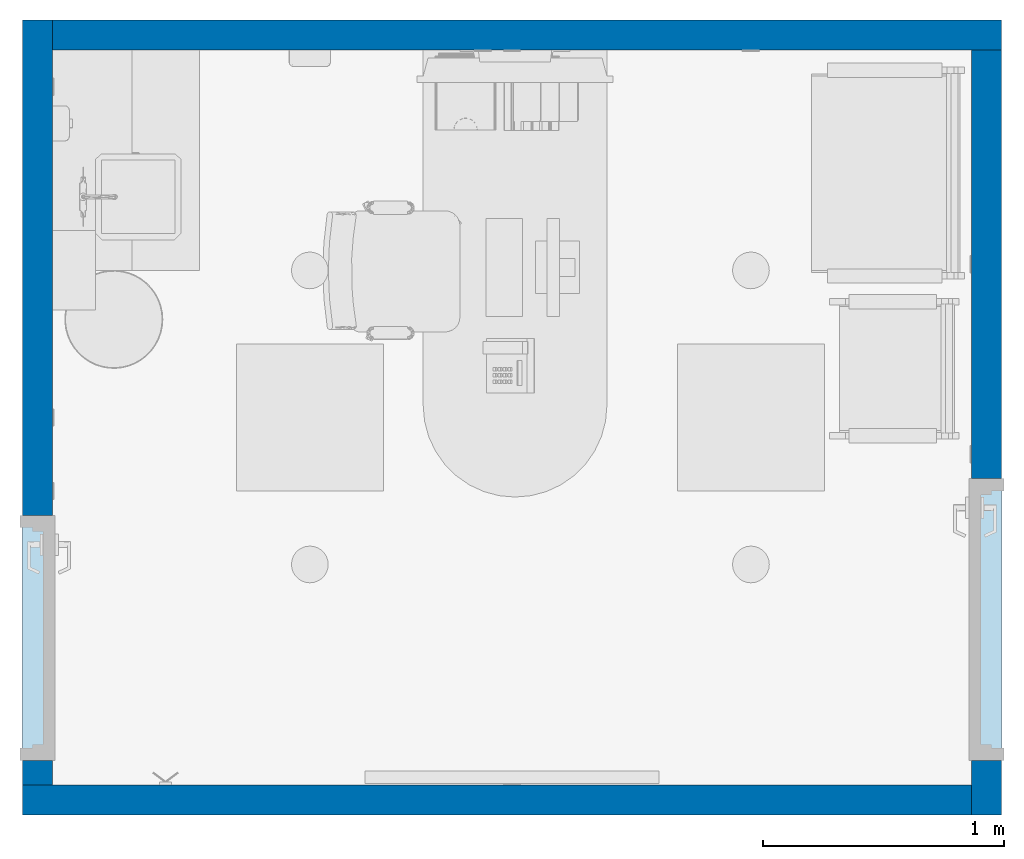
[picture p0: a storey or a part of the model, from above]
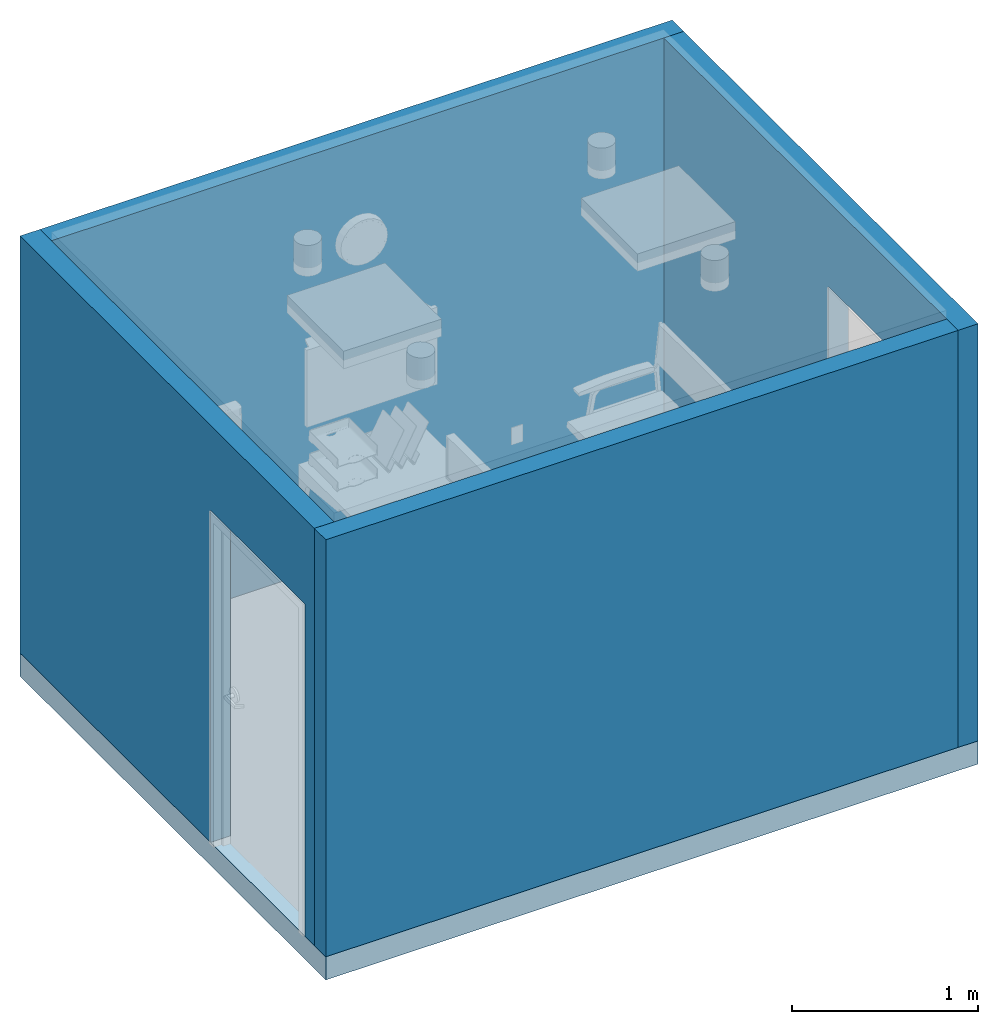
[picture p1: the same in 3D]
Properties of the parts of a building model (IFC2X3)

# File
Description: ViewDefinition [CoordinationView_V2.0]
File name: (ROOM CODE)
Time: 2018-06-27T16:41:24
Written by: The EXPRESS Data Manager Version 5.02.0100.07 : 28 Aug 2013
Made in: 20170223_1515(x64) - Exporter 18.0.0.420 - Alternate UI 18.0.0.420
Comment: STEP Physical File produced by: The EXPRESS Data Manager Version 5.02.0100.07 : 28 Aug 2013 * Module: EDMstepFileFactory/EDMstandAlone * Creation date: Wed Jun 27 16:41:24 2018 * Host: L106-OKC * Database: C:\Users\BHR~1.SPU\AppData\Local\Temp\{47063BCD-B4B2-4790-9621-44DDCE2818D9}\ifc * Database version: 5507 * Database creation date: Wed Jun 27 16:41:22 2018 * Schema: IFC2X3 * Model: DataRepository.ifc * Model creation date: Wed Jun 27 16:41:22 2018 * Header model: DataRepository.ifc_HeaderModel * Header model creation date: Wed Jun 27 16:41:22 2018 * EDMuser: sdai-user * EDMgroup: sdai-group * License ID and type: 5605 : Permanent license. Expiry date: * EDMstepFileFactory options: 020000

# IfcProject, (ROOM CODE)
LongName: ROOM NAME (ROOM CODE); Phase: DRAFT

# IfcSite, Default
RefLatitude: 42, 21, 31, 181945; RefLongitude: -71, -3, -24, -263305; RefElevation: 0 ft

# IfcBuilding, OUTPATIENT / PACT CLINIC (Ch. 265)
LongName: OUTPATIENT / PACT CLINIC (Ch. 265)
Pset_BuildingCommon - NumberOfStoreys: 1

# IfcBuildingStorey, DATUM
In: OUTPATIENT / PACT CLINIC (Ch. 265)
LongName: DATUM; Elevation: 0 ft

# IfcSpace, OFDC2
In: DATUM
LongName: CONSULT ROOM; InteriorOrExteriorSpace: INTERNAL
Pset_SpaceCommon - Reference: CONSULT ROOM OFDC2; Category: Rooms

# IfcBuildingElementProxy: 24" x 24", Supply Diffuser:24" x 24":774819
In: OFDC2
Type - Classification: D3040100 Air Distribution Systems (Uniformat)
Pset_BuildingElementProxyCommon - Reference: 24" x 24"

# IfcBuildingElementProxy: 24" x 24", Return Register:24" x 24":774793
In: OFDC2
Type - Classification: D3040200 Exhaust Ventilation Systems (Uniformat)
Pset_BuildingElementProxyCommon - Reference: 24" x 24"

# IfcBuildingElementProxy: A1015 Telephone_Desk Multi-Line, A1015 - Telephone, Desk, Multiple Line:A1015 Telephone_Desk Multi-Line:1867700
In: OFDC2
Type - Classification: VV (Uniformat)
Pset_BuildingElementProxyCommon - Reference: A1015 Telephone_Desk Multi-Line

# IfcBuildingElementProxy: A5075 - Dispenser, Soap, A5075 - Dispenser, Soap:A5075 - Dispenser, Soap:1867712
In: OFDC2
Classification: VV (Uniformat)
Pset_BuildingElementProxyCommon - Reference: A5075 - Dispenser, Soap

# IfcBuildingElementProxy: A5077 Dispenser_Hand Sanitzer, Hands free, A5077 Dispenser_Hand Sanitzer, Hands free:A5077 Dispenser_Hand Sanitzer, Hands free:1867705
In: OFDC2
Type - Classification: VV (Uniformat)
Pset_BuildingElementProxyCommon - Reference: A5077 Dispenser_Hand Sanitzer, Hands free

# IfcBuildingElementProxy: A5080 - Dispenser, Paper Towel, A5080 - Dispenser, Paper Towel:A5080 - Dispenser, Paper Towel:1867711
In: OFDC2
Classification: CC (Uniformat)
Pset_BuildingElementProxyCommon - Reference: A5080 - Dispenser, Paper Towel

# IfcBuildingElementProxy: A5145 - Hook, Garment, Double, A5145 - Hook, Garment, Double:A5145 - Hook, Garment, Double:1867715
In: OFDC2
Type - Classification: CC (Uniformat)
Pset_BuildingElementProxyCommon - Reference: A5145 - Hook, Garment, Double

# IfcBuildingElementProxy: A5212 - Bracket, Television, Wall-Mounted, Tilt/Angle 32"x 4", A5212 - Bracket, Television, Wall-Mounted, TiltAngle 32x 4:A5212 - Bracket, Television, Wall-Mounted, Tilt/Angle 32"x 4":1867704
In: OFDC2
Type - Classification: VV (Uniformat)
Pset_BuildingElementProxyCommon - Reference: A5212 - Bracket, Television, Wall-Mounted, Tilt/Angle 32"x 4"

# IfcBuildingElementProxy: A5220 - Bracket, Television, Wall Backing, A5220 - Bracket, Television, Wall Backing:A5220 - Bracket, Television, Wall Backing:1867703
In: OFDC2
Type - Classification: CC (Uniformat)
Pset_BuildingElementProxyCommon - Reference: A5220 - Bracket, Television, Wall Backing

# IfcBuildingElementProxy: CD040 - Cabinet, W-H, 2 Shelf, 2 DO, Sloping Top, 38x36x13, CD040 - Cabinet, W-H, 2 Shelf, 2 DO, Sloping Top, 38x36x13:CD040 - Cabinet, W-H, 2 Shelf, 2 DO, Sloping Top, 38x36x13:1867713
In: OFDC2
Type - Classification: CC (Uniformat)
Pset_BuildingElementProxyCommon - Reference: CD040 - Cabinet, W-H, 2 Shelf, 2 DO, Sloping Top, 38x36x13

# IfcBuildingElementProxy: CS010 - Sink, SS, Single Compartment, 7.5x12x12 ID, CS010 - Sink, SS, Single Compartment, 7.5x12x12 ID:CS010 - Sink, SS, Single Compartment, 7.5x12x12 ID:1867710
In: OFDC2
Type - Classification: CC (Uniformat)
Pset_BuildingElementProxyCommon - Reference: CS010 - Sink, SS, Single Compartment, 7.5x12x12 ID

# IfcBuildingElementProxy: CT020 - Countertop, Solid Surface, CT020 - Countertop, Solid Surface:CT020 - Countertop, Solid Surface:1867709
In: OFDC2
Type - Classification: CC (Uniformat)
Pset_BuildingElementProxyCommon - Reference: CT020 - Countertop, Solid Surface

# IfcBuildingElementProxy: Duplex (6)
In: OFDC2
Pset_BuildingElementProxyCommon - Reference: Duplex
Name (Outlet, Duplex, Wall:Duplex:...)
1523865
1532874
1533012
1533116
1870652
1941387

# IfcBuildingElementProxy: E0063 - Workstation, L-Shaped wPeninsula, Wall Mtd, 72x72 (1), E0063 - Workstation, L-Shaped wPeninsula, Wall Mtd, 72x72 (1):E0063 - Workstation, L-Shaped wPeninsula, Wall Mtd, 72x72 (1):1867707
In: OFDC2
Pset_BuildingElementProxyCommon - Reference: E0063 - Workstation, L-Shaped wPeninsula, Wall Mtd, 72x72 (1)

# IfcBuildingElementProxy: F0205 - Chair, Side With Arms, F0205 - Chair, Side With Arms:F0205 - Chair, Side With Arms:1867714
In: OFDC2
Type - Classification: VV (Uniformat)
Pset_BuildingElementProxyCommon - Reference: F0205 - Chair, Side With Arms

# IfcBuildingElementProxy: F0206 - Chair, Side, Bariatric, With Arms, F0206 - Chair, Side, Bariatric, With Arms:F0206 - Chair, Side, Bariatric, With Arms:1867699
In: OFDC2
Type - Classification: VV (Uniformat)
Pset_BuildingElementProxyCommon - Reference: F0206 - Chair, Side, Bariatric, With Arms

# IfcBuildingElementProxy: F0300 - Chair, Task, Swivel, With Arms, F0300 - Chair, Task, Swivel, With Arms:F0300 - Chair, Task, Swivel, With Arms:1867702
In: OFDC2
Type - Classification: VV (Uniformat)
Pset_BuildingElementProxyCommon - Reference: F0300 - Chair, Task, Swivel, With Arms

# IfcBuildingElementProxy: F2000 - Basket, Wastepaper, F2000 - Basket, Wastepaper:F2000 - Basket, Wastepaper:1867701
In: OFDC2
Type - Classification: VV (Uniformat)
Pset_BuildingElementProxyCommon - Reference: F2000 - Basket, Wastepaper

# IfcBuildingElementProxy: F3065 - Whiteboard/Bulletin Board, Combination, F3065 - WhiteboardBulletin Board Combination:F3065 - Whiteboard/Bulletin Board, Combination:1867706
In: OFDC2
Type - Material: Wood, Plastic, Opaque White
Pset_BuildingElementProxyCommon - Reference: F3065 - Whiteboard/Bulletin Board, Combination

# IfcBuildingElementProxy: F3200 - Clock, Battery, 12in Dia, F3200 - Clock, Battery, 12in Dia:F3200 - Clock, Battery, 12in Dia:1867698
In: OFDC2
Type - Classification: VV (Uniformat)
Pset_BuildingElementProxyCommon - Reference: F3200 - Clock, Battery, 12in Dia

# IfcBuildingElementProxy: M1801 - Computer with Flat Panel Monitor, M1801 - Computer with Flat Panel Monitor:M1801 - Computer with Flat Panel Monitor:1867708
In: OFDC2
Type - Classification: VV (Uniformat)
Pset_BuildingElementProxyCommon - Reference: M1801 - Computer with Flat Panel Monitor

# IfcBuildingElementProxy: Single (2)
In: OFDC2
Pset_BuildingElementProxyCommon - Reference: Single
Name (Switch, Single:Single:...)
1870864
1870914

# IfcBuildingElementProxy: Telephone/Data, Outlet, Communications:Telephone/Data:1870618
In: OFDC2
Pset_BuildingElementProxyCommon - Reference: Telephone/Data

# IfcCovering: Compound Ceiling:2' x 2' ACT System, Compound Ceiling:2' x 2' ACT System:774780
In: DATUM
PredefinedType: CEILING; Classification: C3030210 Suspended Ceilings - Acoustical (Uniformat); Material: <Unnamed> 0.135417 ft, Acoustic Ceiling Tile 24 x 24 0.0520833 ft
Pset_CoveringCommon - Reference: 2' x 2' ACT System; Finish: Acoustic Ceiling Tile 24 x 24;; TotalThickness: 0.1875 ft

# IfcDoor: 36" x 84", Single - Flush:36" x 84":1867544
In: DATUM
Type - ParameterTakesPrecedence: no; Sizeable: no; Classification: C1020 Interior Doors (Uniformat)
OverallHeight: 7.16667 ft; OverallWidth: 3.33333 ft
Pset_DoorCommon - IsExternal: no; Reference: 36" x 84"

# IfcDoor: 42" x 84", Single - Flush:42" x 84":1867172
In: DATUM
Type - ParameterTakesPrecedence: no; Sizeable: no; Classification: C1020 Interior Doors (Uniformat)
OverallHeight: 7.16667 ft; OverallWidth: 3.83333 ft
Pset_DoorCommon - IsExternal: no; Reference: 42" x 84"

# IfcFlowTerminal: 6" (4)
In: OFDC2
Type - Classification: D5020220 Lighting - Incandescent (Uniformat)
Pset_DistributionFlowElementCommon - Reference: 6"
Name (Downlight - Recessed Can:6":...)
1871293
1871367
1871467
1871557

# IfcSlab: Floor:Generic - 6", Floor:Generic - 6":774787
In: DATUM
PredefinedType: FLOOR; Classification: B1010 Floor Construction (Uniformat); Material: <Unnamed> 0.5 ft
Pset_SlabCommon - Reference: Generic - 6"; IsExternal: no; LoadBearing: no; PitchAngle: 0 deg

# IfcWallStandardCase: Basic Wall:Interior - 4 7/8" (4)
In: DATUM
Type - PredefinedType: STANDARD; Material: <Unnamed> 0.40625 ft
Classification: B2010 Exterior Walls (Uniformat)
Pset_WallCommon - LoadBearing: no; Reference: Interior - 4 7/8"; ExtendToStructure: no; IsExternal: yes
Name (Basic Wall:Interior - 4 7/8":...)
1406484
1406487
1406490
1406493
